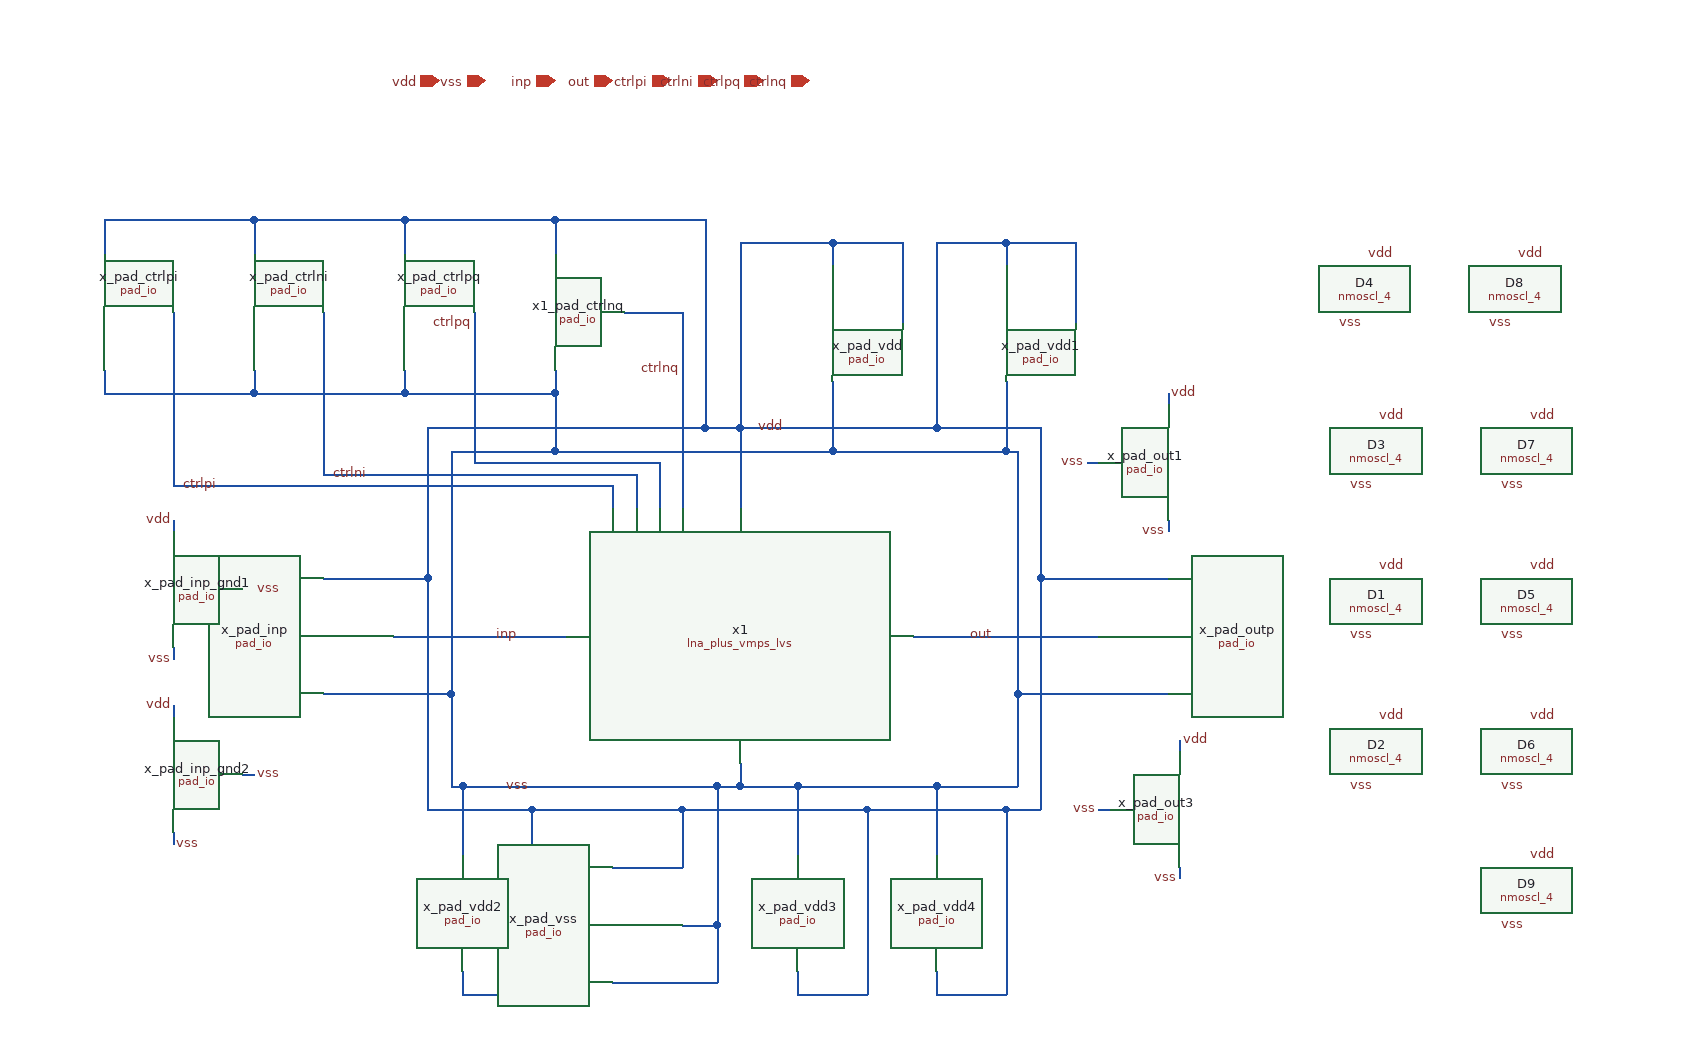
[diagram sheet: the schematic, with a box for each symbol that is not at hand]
v {xschem version=3.4.8RC file_version=1.3}
G {}
K {}
V {}
S {}
F {}
E {}
N 5430 -1750 5590 -1750 {lab=out}
N 5280 -1930 5280 -1860 {lab=vdd}
N 4980 -1750 5130 -1750 {lab=inp}
N 4920 -1800 5010 -1800 {lab=vdd}
N 5010 -1930 5010 -1800 {lab=vdd}
N 5250 -1930 5280 -1930 {lab=vdd}
N 5450 -1930 5540 -1930 {lab=vdd}
N 5010 -1800 5010 -1600 {lab=vdd}
N 5540 -1800 5650 -1800 {lab=vdd}
N 5280 -2090 5280 -1930 {lab=vdd}
N 5280 -2090 5360 -2090 {lab=vdd}
N 5360 -2090 5360 -2070 {lab=vdd}
N 5170 -1550 5230 -1550 {lab=vdd}
N 4920 -1700 5030 -1700 {lab=vss}
N 5030 -1910 5030 -1700 {lab=vss}
N 5510 -1910 5520 -1910 {lab=vss}
N 5030 -1700 5030 -1620 {lab=vss}
N 5360 -1970 5360 -1910 {lab=vss}
N 5520 -1700 5650 -1700 {lab=vss}
N 5540 -1930 5540 -1800 {lab=vdd}
N 5520 -1910 5520 -1700 {lab=vss}
N 5540 -1800 5540 -1600 {lab=vdd}
N 5520 -1700 5520 -1620 {lab=vss}
N 5260 -1620 5280 -1620 {lab=vss}
N 5230 -1600 5230 -1550 {lab=vdd}
N 5510 -1600 5540 -1600 {lab=vdd}
N 5280 -1640 5280 -1620 {lab=vss}
N 5230 -1500 5260 -1500 {lab=vss}
N 5260 -1620 5260 -1500 {lab=vss}
N 5450 -1620 5520 -1620 {lab=vss}
N 5170 -1450 5260 -1450 {lab=vss}
N 5260 -1500 5260 -1450 {lab=vss}
N 5360 -2090 5420 -2090 {lab=vdd}
N 5420 -2090 5420 -2020 {lab=vdd}
N 4730 -2110 4730 -2080 {lab=vdd}
N 4990 -2110 5120 -2110 {lab=vdd}
N 5120 -2110 5120 -2080 {lab=vdd}
N 4990 -2110 4990 -2080 {lab=vdd}
N 4860 -2110 4990 -2110 {lab=vdd}
N 4860 -2110 4860 -2080 {lab=vdd}
N 4730 -2110 4860 -2110 {lab=vdd}
N 5120 -2110 5250 -2110 {lab=vdd}
N 5120 -1910 5360 -1910 {lab=vss}
N 4730 -1980 4730 -1960 {lab=vss}
N 4990 -1960 5120 -1960 {lab=vss}
N 5120 -1980 5120 -1960 {lab=vss}
N 4860 -1980 4860 -1960 {lab=vss}
N 4730 -1960 4860 -1960 {lab=vss}
N 4990 -1980 4990 -1960 {lab=vss}
N 4860 -1960 4990 -1960 {lab=vss}
N 5120 -1960 5120 -1910 {lab=vss}
N 5030 -1910 5120 -1910 {lab=vss}
N 5250 -2110 5250 -1930 {lab=vdd}
N 5010 -1930 5250 -1930 {lab=vdd}
N 5230 -2030 5230 -1860 {lab=ctrlnq}
N 5180 -2030 5230 -2030 {lab=ctrlnq}
N 5050 -2030 5050 -1900 {lab=ctrlpq}
N 5050 -1900 5210 -1900 {lab=ctrlpq}
N 5210 -1900 5210 -1860 {lab=ctrlpq}
N 4920 -2030 4920 -1890 {lab=ctrlni}
N 4920 -1890 5190 -1890 {lab=ctrlni}
N 5190 -1890 5190 -1860 {lab=ctrlni}
N 4790 -2030 4790 -1880 {lab=ctrlpi}
N 4790 -1880 5170 -1880 {lab=ctrlpi}
N 5170 -1880 5170 -1860 {lab=ctrlpi}
N 4790 -1740 4790 -1730 {lab=vss}
N 4850 -1790 4860 -1790 {lab=vss}
N 4790 -1850 4790 -1840 {lab=vdd}
N 4790 -1690 4790 -1680 {lab=vdd}
N 4850 -1630 4860 -1630 {lab=vss}
N 4790 -1580 4790 -1570 {lab=vss}
N 5650 -1960 5650 -1950 {lab=vdd}
N 5580 -1900 5590 -1900 {lab=vss}
N 5650 -1850 5650 -1840 {lab=vss}
N 5660 -1660 5660 -1650 {lab=vdd}
N 5590 -1600 5600 -1600 {lab=vss}
N 5660 -1550 5660 -1540 {lab=vss}
N 5510 -2090 5510 -2070 {lab=vdd}
N 5510 -1970 5510 -1910 {lab=vss}
N 5510 -2090 5570 -2090 {lab=vdd}
N 5570 -2090 5570 -2020 {lab=vdd}
N 5360 -1910 5510 -1910 {lab=vss}
N 5450 -2090 5510 -2090 {lab=vdd}
N 5450 -2090 5450 -1930 {lab=vdd}
N 5280 -1930 5450 -1930 {lab=vdd}
N 5040 -1460 5040 -1440 {lab=vdd}
N 5040 -1620 5040 -1560 {lab=vss}
N 5040 -1440 5100 -1440 {lab=vdd}
N 5100 -1600 5100 -1440 {lab=vdd}
N 5030 -1620 5040 -1620 {lab=vss}
N 5010 -1600 5100 -1600 {lab=vdd}
N 5100 -1600 5230 -1600 {lab=vdd}
N 5040 -1620 5260 -1620 {lab=vss}
N 5330 -1460 5330 -1440 {lab=vdd}
N 5330 -1620 5330 -1560 {lab=vss}
N 5330 -1440 5390 -1440 {lab=vdd}
N 5390 -1600 5390 -1440 {lab=vdd}
N 5280 -1620 5330 -1620 {lab=vss}
N 5230 -1600 5390 -1600 {lab=vdd}
N 5450 -1460 5450 -1440 {lab=vdd}
N 5450 -1620 5450 -1560 {lab=vss}
N 5450 -1440 5510 -1440 {lab=vdd}
N 5510 -1600 5510 -1440 {lab=vdd}
N 5330 -1620 5450 -1620 {lab=vss}
N 5390 -1600 5510 -1600 {lab=vdd}
C {06_integ/pad_io.sym} 4920 -1750 0 0 {name=x_pad_inp
}
C {06_integ/pad_io.sym} 5170 -1500 0 0 {name=x_pad_vss}
C {06_integ/pad_io.sym} 5650 -1750 0 1 {name=x_pad_outp}
C {06_integ/pad_io.sym} 5360 -2020 0 0 {name=x_pad_vdd}
C {06_integ/pad_io.sym} 4730 -2030 0 0 {name=x_pad_ctrlpi}
C {06_integ/pad_io.sym} 4860 -2030 0 0 {name=x_pad_ctrlni}
C {06_integ/pad_io.sym} 4990 -2030 0 0 {name=x_pad_ctrlpq}
C {06_integ/pad_io.sym} 5120 -2030 0 0 {name=x1_pad_ctrlnq}
C {lab_wire.sym} 5100 -1620 0 0 {name=p1 sig_type=std_logic lab=vss}
C {lab_wire.sym} 5090 -1750 0 0 {name=p3 sig_type=std_logic lab=inp}
C {lab_wire.sym} 5500 -1750 0 0 {name=p4 sig_type=std_logic lab=out}
C {lab_wire.sym} 5320 -1930 0 0 {name=p2 sig_type=std_logic lab=vdd}
C {lab_wire.sym} 4830 -1880 0 0 {name=p6 sig_type=std_logic lab=ctrlpi}
C {lab_wire.sym} 4960 -1890 0 0 {name=p7 sig_type=std_logic lab=ctrlni}
C {lab_wire.sym} 5050 -2020 1 1 {name=p8 sig_type=std_logic lab=ctrlpq}
C {lab_wire.sym} 5230 -1980 3 1 {name=p9 sig_type=std_logic lab=ctrlnq}
C {06_integ/pad_io.sym} 4790 -1790 0 0 {name=x_pad_inp_gnd1
}
C {06_integ/pad_io.sym} 4790 -1630 0 0 {name=x_pad_inp_gnd2
}
C {lab_wire.sym} 4790 -1850 0 0 {name=p10 sig_type=std_logic lab=vdd}
C {lab_wire.sym} 4790 -1730 0 0 {name=p11 sig_type=std_logic lab=vss}
C {lab_wire.sym} 4860 -1790 0 1 {name=p12 sig_type=std_logic lab=vss}
C {lab_wire.sym} 4860 -1630 0 1 {name=p13 sig_type=std_logic lab=vss}
C {lab_wire.sym} 4790 -1570 0 1 {name=p14 sig_type=std_logic lab=vss}
C {lab_wire.sym} 4790 -1690 0 0 {name=p15 sig_type=std_logic lab=vdd}
C {06_integ/pad_io.sym} 5650 -1900 0 1 {name=x_pad_out1

}
C {lab_wire.sym} 5580 -1900 0 0 {name=p16 sig_type=std_logic lab=vss}
C {lab_wire.sym} 5650 -1840 0 0 {name=p17 sig_type=std_logic lab=vss}
C {lab_wire.sym} 5650 -1960 0 1 {name=p18 sig_type=std_logic lab=vdd}
C {06_integ/pad_io.sym} 5660 -1600 0 1 {name=x_pad_out3
}
C {lab_wire.sym} 5590 -1600 0 0 {name=p22 sig_type=std_logic lab=vss}
C {lab_wire.sym} 5660 -1540 0 0 {name=p23 sig_type=std_logic lab=vss}
C {lab_wire.sym} 5660 -1660 0 1 {name=p24 sig_type=std_logic lab=vdd}
C {06_integ/lna_plus_vmps_lvs.sym} 5270 -1750 0 0 {name=x1}
C {06_integ/pad_io.sym} 5510 -2020 0 0 {name=x_pad_vdd1}
C {sg13g2_pr/nmoscl_4.sym} 5830 -1780 0 0 {name=D1
model=nmoscl_4
m=1
spiceprefix=X
}
C {lab_wire.sym} 5830 -1810 0 1 {name=p5 sig_type=std_logic lab=vdd}
C {lab_wire.sym} 5830 -1750 0 0 {name=p19 sig_type=std_logic lab=vss}
C {sg13g2_pr/nmoscl_4.sym} 5830 -1650 0 0 {name=D2
model=nmoscl_4
m=1
spiceprefix=X
}
C {lab_wire.sym} 5830 -1680 0 1 {name=p20 sig_type=std_logic lab=vdd}
C {lab_wire.sym} 5830 -1620 0 0 {name=p21 sig_type=std_logic lab=vss}
C {sg13g2_pr/nmoscl_4.sym} 5830 -1910 0 0 {name=D3
model=nmoscl_4
m=1
spiceprefix=X
}
C {lab_wire.sym} 5830 -1940 0 1 {name=p25 sig_type=std_logic lab=vdd}
C {lab_wire.sym} 5830 -1880 0 0 {name=p26 sig_type=std_logic lab=vss}
C {sg13g2_pr/nmoscl_4.sym} 5820 -2050 0 0 {name=D4
model=nmoscl_4
m=1
spiceprefix=X
}
C {lab_wire.sym} 5820 -2080 0 1 {name=p27 sig_type=std_logic lab=vdd}
C {lab_wire.sym} 5820 -2020 0 0 {name=p28 sig_type=std_logic lab=vss}
C {sg13g2_pr/nmoscl_4.sym} 5960 -1780 0 0 {name=D5
model=nmoscl_4
m=1
spiceprefix=X
}
C {lab_wire.sym} 5960 -1810 0 1 {name=p29 sig_type=std_logic lab=vdd}
C {lab_wire.sym} 5960 -1750 0 0 {name=p30 sig_type=std_logic lab=vss}
C {sg13g2_pr/nmoscl_4.sym} 5960 -1650 0 0 {name=D6
model=nmoscl_4
m=1
spiceprefix=X
}
C {lab_wire.sym} 5960 -1680 0 1 {name=p31 sig_type=std_logic lab=vdd}
C {lab_wire.sym} 5960 -1620 0 0 {name=p32 sig_type=std_logic lab=vss}
C {sg13g2_pr/nmoscl_4.sym} 5960 -1910 0 0 {name=D7
model=nmoscl_4
m=1
spiceprefix=X
}
C {lab_wire.sym} 5960 -1940 0 1 {name=p33 sig_type=std_logic lab=vdd}
C {lab_wire.sym} 5960 -1880 0 0 {name=p34 sig_type=std_logic lab=vss}
C {sg13g2_pr/nmoscl_4.sym} 5950 -2050 0 0 {name=D8
model=nmoscl_4
m=1
spiceprefix=X
}
C {lab_wire.sym} 5950 -2080 0 1 {name=p35 sig_type=std_logic lab=vdd}
C {lab_wire.sym} 5950 -2020 0 0 {name=p36 sig_type=std_logic lab=vss}
C {sg13g2_pr/nmoscl_4.sym} 5960 -1530 0 0 {name=D9
model=nmoscl_4
m=1
spiceprefix=X
}
C {lab_wire.sym} 5960 -1560 0 1 {name=p37 sig_type=std_logic lab=vdd}
C {lab_wire.sym} 5960 -1500 0 0 {name=p38 sig_type=std_logic lab=vss}
C {06_integ/pad_io.sym} 5040 -1510 2 1 {name=x_pad_vdd2}
C {06_integ/pad_io.sym} 5330 -1510 2 1 {name=x_pad_vdd3}
C {06_integ/pad_io.sym} 5450 -1510 2 1 {name=x_pad_vdd4}
C {iopin.sym} 5020 -2230 3 0 {name=p97 lab=vdd}
C {iopin.sym} 5060 -2230 3 0 {name=p98 lab=vss}
C {iopin.sym} 5120 -2230 3 0 {name=p99 lab=inp}
C {iopin.sym} 5170 -2230 3 0 {name=p39 lab=out}
C {iopin.sym} 5220 -2230 3 0 {name=p40 lab=ctrlpi}
C {iopin.sym} 5260 -2230 3 0 {name=p41 lab=ctrlni}
C {iopin.sym} 5300 -2230 3 0 {name=p42 lab=ctrlpq}
C {iopin.sym} 5340 -2230 3 0 {name=p43 lab=ctrlnq}
